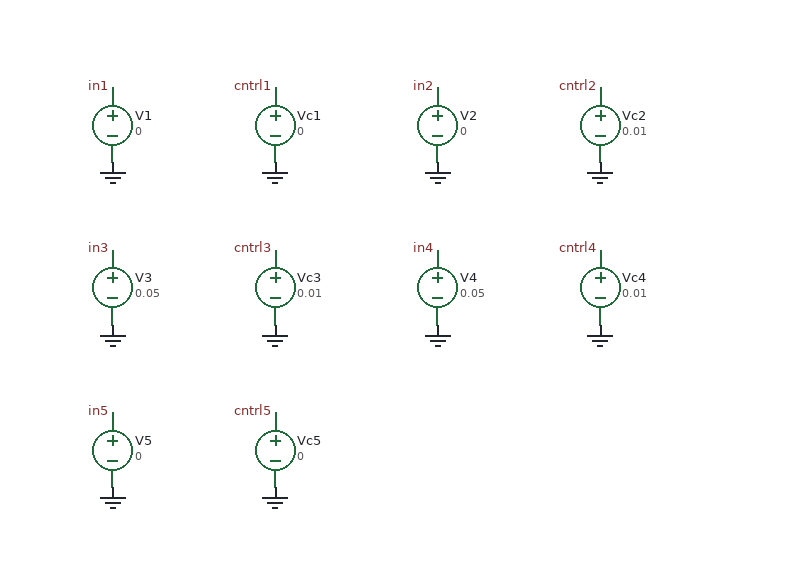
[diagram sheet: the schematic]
v {xschem version=3.4.5 file_version=1.2}
G {}
K {}
V {}
S {}
E {}
C {devices/vsource.sym} 300 150 0 0 {name=V1
value=0}
C {devices/vsource.sym} 430 150 0 0 {name=Vc1
value=0}
C {devices/vsource.sym} 560 150 0 0 {name=V2
value=0}
C {devices/vsource.sym} 690 150 0 0 {name=Vc2
value=0.01}
C {devices/vsource.sym} 300 280 0 0 {name=V3
value=0.05}
C {devices/vsource.sym} 430 280 0 0 {name=Vc3
value=0.01}
C {devices/vsource.sym} 560 280 0 0 {name=V4
value=0.05}
C {devices/vsource.sym} 690 280 0 0 {name=Vc4
value=0.01}
C {devices/vsource.sym} 300 410 0 0 {name=V5
value=0}
C {devices/vsource.sym} 430 410 0 0 {name=Vc5
value=0}
C {devices/lab_pin.sym} 300 120 0 0 {name=l_in1 sig_type=std_logic lab=in1}
C {devices/gnd.sym} 300 180 0 0 {name=l_0 lab=GND}
C {devices/gnd.sym} 430 180 0 0 {name=l_0 lab=GND}
C {devices/gnd.sym} 560 180 0 0 {name=l_0 lab=GND}
C {devices/gnd.sym} 690 180 0 0 {name=l_0 lab=GND}
C {devices/gnd.sym} 300 310 0 0 {name=l_0 lab=GND}
C {devices/gnd.sym} 430 310 0 0 {name=l_0 lab=GND}
C {devices/gnd.sym} 560 310 0 0 {name=l_0 lab=GND}
C {devices/gnd.sym} 690 310 0 0 {name=l_0 lab=GND}
C {devices/gnd.sym} 300 440 0 0 {name=l_0 lab=GND}
C {devices/gnd.sym} 430 440 0 0 {name=l_0 lab=GND}
C {devices/lab_pin.sym} 430 120 0 0 {name=l_cntrl1 sig_type=std_logic lab=cntrl1}
C {devices/lab_pin.sym} 560 120 0 0 {name=l_in2 sig_type=std_logic lab=in2}
C {devices/lab_pin.sym} 690 120 0 0 {name=l_cntrl2 sig_type=std_logic lab=cntrl2}
C {devices/lab_pin.sym} 300 250 0 0 {name=l_in3 sig_type=std_logic lab=in3}
C {devices/lab_pin.sym} 430 250 0 0 {name=l_cntrl3 sig_type=std_logic lab=cntrl3}
C {devices/lab_pin.sym} 560 250 0 0 {name=l_in4 sig_type=std_logic lab=in4}
C {devices/lab_pin.sym} 690 250 0 0 {name=l_cntrl4 sig_type=std_logic lab=cntrl4}
C {devices/lab_pin.sym} 300 380 0 0 {name=l_in5 sig_type=std_logic lab=in5}
C {devices/lab_pin.sym} 430 380 0 0 {name=l_cntrl5 sig_type=std_logic lab=cntrl5}
